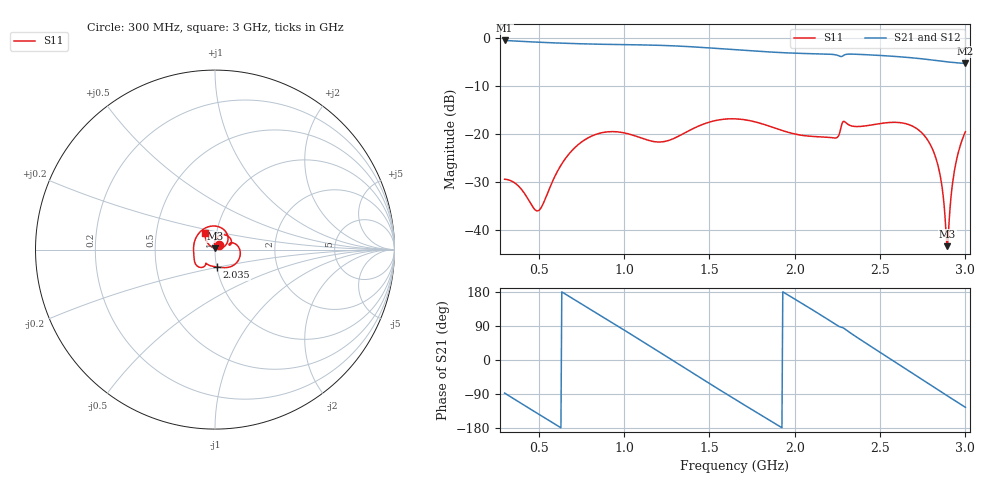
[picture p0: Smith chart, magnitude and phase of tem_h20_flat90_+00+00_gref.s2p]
! tem_h20_flat90_+00+00_gref
! simulated by sim/fixtures_fdtd.py (S12 = S21, S22 not computed)
# HZ S RI R 50
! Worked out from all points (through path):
!   541 points, 300 MHz to 3 GHz, reference 50 ohm
!   highest |S21| = -0.48 dB at 300 MHz (marker M1); lowest = -5.3 dB at 3 GHz (marker M2)
!   group delay of S21, straight-line fit = 776 ps
!   lowest |S11| = -43.4 dB at 2.895 GHz (marker M3), VSWR 1.01, Z = 50 + j0.674 ohm
!   |S11| at or under -10 dB: start of sweep to end of sweep
!   |S22| runs from - to - dB; largest |S21 - S12| = 0
!   S11 on the Smith chart (normalised r, x): 300 MHz: 1.05, +0.05; 2.035 GHz: 1.00, -0.20; 3 GHz: 0.88, +0.16
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3e8  0.0242 0.0234  0.0452 -0.9456  0.0452 -0.9456  0 0
5e8  0.00702 0.0143  -0.7252 -0.5451  -0.7252 -0.5451  0 0
6.25e8  -0.00264 0.0455  -0.8875 -0.0383  -0.8875 -0.0383  0 0
7.5e8  0.0249 0.0784  -0.742 0.4614  -0.742 0.4614  0 0
8.65e8  0.0665 0.0782  -0.3855 0.7733  -0.3855 0.7733  0 0
9.75e8  0.0901 0.053  0.0586 0.8556  0.0586 0.8556  0 0
1.08e9  0.0886 0.0299  0.4669 0.7127  0.4669 0.7127  0 0
1.2e9  0.0781 0.0264  0.7764 0.3281  0.7764 0.3281  0 0
1.32e9  0.0877 0.0366  0.8114 -0.1602  0.8114 -0.1602  0 0
1.455e9  0.1223 0.0252  0.5218 -0.6077  0.5218 -0.6077  0 0
1.65e9  0.1346 -0.0508  -0.1787 -0.7363  -0.1787 -0.7363  0 0
1.85e9  0.0683 -0.0998  -0.6678 -0.2644  -0.6678 -0.2644  0 0
2.035e9  0.0115 -0.0966  -0.6091 0.3327  -0.6091 0.3327  0 0
2.1e9  -0.00804 -0.0941  -0.4746 0.5002  -0.4746 0.5002  0 0
2.32e9  -0.1171 -0.0401  0.1953 0.6534  0.1953 0.6534  0 0
2.55e9  -0.0541 0.1201  0.6488 0.0636  0.6488 0.0636  0 0
2.66e9  0.0316 0.1228  0.5633 -0.2824  0.5633 -0.2824  0 0
2.795e9  0.0676 0.0373  0.2403 -0.5443  0.2403 -0.5443  0 0
2.85e9  0.0376 0.00888  0.08 -0.573  0.08 -0.573  0 0
2.895e9  0.00048 0.00673  -0.0479 -0.5639  -0.0479 -0.5639  0 0
2.94e9  -0.035 0.0292  -0.1679 -0.5294  -0.1679 -0.5294  0 0
3e9  -0.0555 0.0899  -0.3108 -0.4472  -0.3108 -0.4472  0 0
